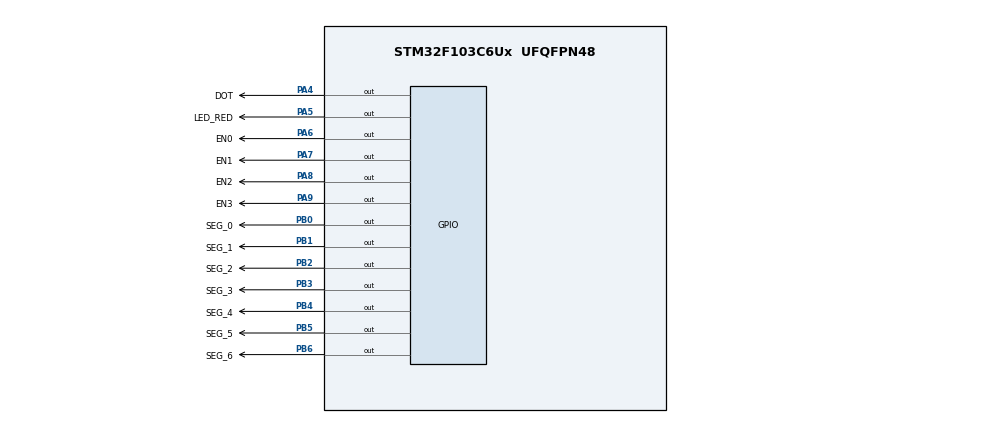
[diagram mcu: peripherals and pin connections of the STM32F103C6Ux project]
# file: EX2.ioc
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Mcu.Family=STM32F1
Mcu.Name=STM32F103C6Ux
Mcu.Package=UFQFPN48
NVIC.PriorityGroup=NVIC_PRIORITYGROUP_4
NVIC.TIM2_IRQn=true\:0\:0\:false\:false\:true\:true\:true
PA4.GPIO_Label=DOT
PA4.Signal=GPIO_Output
PA5.GPIO_Label=LED_RED
PA5.Signal=GPIO_Output
PA6.GPIO_Label=EN0
PA6.Signal=GPIO_Output
PA7.GPIO_Label=EN1
PA7.Signal=GPIO_Output
PA8.GPIO_Label=EN2
PA8.Signal=GPIO_Output
PA9.GPIO_Label=EN3
PA9.Signal=GPIO_Output
PB0.GPIO_Label=SEG_0
PB0.Signal=GPIO_Output
PB1.GPIO_Label=SEG_1
PB1.Signal=GPIO_Output
PB2.GPIO_Label=SEG_2
PB2.Signal=GPIO_Output
PB3.GPIO_Label=SEG_3
PB3.Signal=GPIO_Output
PB4.GPIO_Label=SEG_4
PB4.Signal=GPIO_Output
PB5.GPIO_Label=SEG_5
PB5.Signal=GPIO_Output
PB6.GPIO_Label=SEG_6
PB6.Signal=GPIO_Output
ProjectManager.HeapSize=0x200
ProjectManager.StackSize=0x400
ProjectManager.TargetToolchain=STM32CubeIDE
RCC.APB1Freq_Value=8000000
RCC.APB2Freq_Value=8000000
TIM2.Period=9
TIM2.Prescaler=7999
VP_SYS_VS_ND.Mode=No_Debug
VP_TIM2_VS_ClockSourceINT.Mode=Internal
board=custom

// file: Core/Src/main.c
/* USER CODE BEGIN Header */
/**
  ******************************************************************************
  * @file           : main.c
  * @brief          : Main program body
  ******************************************************************************
  * @attention
  *
  * <h2><center>&copy; Copyright (c) 2022 STMicroelectronics.
  * All rights reserved.</center></h2>
  *
  * This software component is licensed by ST under BSD 3-Clause license,
  * the "License"; You may not use this file except in compliance with the
  * License. You may obtain a copy of the License at:
  *                        opensource.org/licenses/BSD-3-Clause
  *
  ******************************************************************************
  */
/* USER CODE END Header */
#include "main.h"

TIM_HandleTypeDef htim2;

void SystemClock_Config(void);
static void MX_GPIO_Init(void);
static void MX_TIM2_Init(void);

/* USER CODE BEGIN 0 */
void display7SEG(int num){
	  if(num == 0){
		  HAL_GPIO_WritePin(SEG_a_GPIO_Port, SEG_a_Pin, RESET);
		  HAL_GPIO_WritePin(SEG_b_GPIO_Port, SEG_b_Pin, RESET);
		  HAL_GPIO_WritePin(SEG_c_GPIO_Port, SEG_c_Pin, RESET);
		  HAL_GPIO_WritePin(SEG_d_GPIO_Port, SEG_d_Pin, RESET);
		  HAL_GPIO_WritePin(SEG_e_GPIO_Port, SEG_e_Pin, RESET);
		  HAL_GPIO_WritePin(SEG_f_GPIO_Port, SEG_f_Pin, RESET);
		  HAL_GPIO_WritePin(SEG_g_GPIO_Port, SEG_g_Pin, SET);
	  }
	  if(num == 1){
		  HAL_GPIO_WritePin(SEG_a_GPIO_Port, SEG_a_Pin, SET);
		  HAL_GPIO_WritePin(SEG_b_GPIO_Port, SEG_b_Pin, RESET);
		  HAL_GPIO_WritePin(SEG_c_GPIO_Port, SEG_c_Pin, RESET);
		  HAL_GPIO_WritePin(SEG_d_GPIO_Port, SEG_d_Pin, SET);
		  HAL_GPIO_WritePin(SEG_e_GPIO_Port, SEG_e_Pin, SET);
		  HAL_GPIO_WritePin(SEG_f_GPIO_Port, SEG_f_Pin, SET);
		  HAL_GPIO_WritePin(SEG_g_GPIO_Port, SEG_g_Pin, SET);
	  }
	  if(num == 2){
		  HAL_GPIO_WritePin(SEG_a_GPIO_Port, SEG_a_Pin, RESET);
		  HAL_GPIO_WritePin(SEG_b_GPIO_Port, SEG_b_Pin, RESET);
		  HAL_GPIO_WritePin(SEG_c_GPIO_Port, SEG_c_Pin, SET);
		  HAL_GPIO_WritePin(SEG_d_GPIO_Port, SEG_d_Pin, RESET);
		  HAL_GPIO_WritePin(SEG_e_GPIO_Port, SEG_e_Pin, RESET);
		  HAL_GPIO_WritePin(SEG_f_GPIO_Port, SEG_f_Pin, SET);
		  HAL_GPIO_WritePin(SEG_g_GPIO_Port, SEG_g_Pin, RESET);
	  }
	  if(num == 3){
		  HAL_GPIO_WritePin(SEG_a_GPIO_Port, SEG_a_Pin, RESET);
		  HAL_GPIO_WritePin(SEG_b_GPIO_Port, SEG_b_Pin, RESET);
		  HAL_GPIO_WritePin(SEG_c_GPIO_Port, SEG_c_Pin, RESET);
		  HAL_GPIO_WritePin(SEG_d_GPIO_Port, SEG_d_Pin, RESET);
		  HAL_GPIO_WritePin(SEG_e_GPIO_Port, SEG_e_Pin, SET);
		  HAL_GPIO_WritePin(SEG_f_GPIO_Port, SEG_f_Pin, SET);
		  HAL_GPIO_WritePin(SEG_g_GPIO_Port, SEG_g_Pin, RESET);
	  }
	  if(num == 4){
		  HAL_GPIO_WritePin(SEG_a_GPIO_Port, SEG_a_Pin, SET);
		  HAL_GPIO_WritePin(SEG_b_GPIO_Port, SEG_b_Pin, RESET);
		  HAL_GPIO_WritePin(SEG_c_GPIO_Port, SEG_c_Pin, RESET);
		  HAL_GPIO_WritePin(SEG_d_GPIO_Port, SEG_d_Pin, SET);
		  HAL_GPIO_WritePin(SEG_e_GPIO_Port, SEG_e_Pin, SET);
		  HAL_GPIO_WritePin(SEG_f_GPIO_Port, SEG_f_Pin, RESET);
		  HAL_GPIO_WritePin(SEG_g_GPIO_Port, SEG_g_Pin, RESET);
	  }
	  if(num == 5){
		  HAL_GPIO_WritePin(SEG_a_GPIO_Port, SEG_a_Pin, RESET);
		  HAL_GPIO_WritePin(SEG_b_GPIO_Port, SEG_b_Pin, SET);
		  HAL_GPIO_WritePin(SEG_c_GPIO_Port, SEG_c_Pin, RESET);
		  HAL_GPIO_WritePin(SEG_d_GPIO_Port, SEG_d_Pin, RESET);
		  HAL_GPIO_WritePin(SEG_e_GPIO_Port, SEG_e_Pin, SET);
		  HAL_GPIO_WritePin(SEG_f_GPIO_Port, SEG_f_Pin, RESET);
		  HAL_GPIO_WritePin(SEG_g_GPIO_Port, SEG_g_Pin, RESET);
	  }
	  if(num == 6){
		  HAL_GPIO_WritePin(SEG_a_GPIO_Port, SEG_a_Pin, RESET);
		  HAL_GPIO_WritePin(SEG_b_GPIO_Port, SEG_b_Pin, SET);
		  HAL_GPIO_WritePin(SEG_c_GPIO_Port, SEG_c_Pin, RESET);
		  HAL_GPIO_WritePin(SEG_d_GPIO_Port, SEG_d_Pin, RESET);
		  HAL_GPIO_WritePin(SEG_e_GPIO_Port, SEG_e_Pin, RESET);
		  HAL_GPIO_WritePin(SEG_f_GPIO_Port, SEG_f_Pin, RESET);
		  HAL_GPIO_WritePin(SEG_g_GPIO_Port, SEG_g_Pin, RESET);
	  }
	  if(num == 7){
		  HAL_GPIO_WritePin(SEG_a_GPIO_Port, SEG_a_Pin, RESET);
		  HAL_GPIO_WritePin(SEG_b_GPIO_Port, SEG_b_Pin, RESET);
		  HAL_GPIO_WritePin(SEG_c_GPIO_Port, SEG_c_Pin, RESET);
		  HAL_GPIO_WritePin(SEG_d_GPIO_Port, SEG_d_Pin, SET);
		  HAL_GPIO_WritePin(SEG_e_GPIO_Port, SEG_e_Pin, SET);
		  HAL_GPIO_WritePin(SEG_f_GPIO_Port, SEG_f_Pin, SET);
		  HAL_GPIO_WritePin(SEG_g_GPIO_Port, SEG_g_Pin, SET);
	  }
	  if(num == 8){
		  HAL_GPIO_WritePin(SEG_a_GPIO_Port, SEG_a_Pin, RESET);
		  HAL_GPIO_WritePin(SEG_b_GPIO_Port, SEG_b_Pin, RESET);
		  HAL_GPIO_WritePin(SEG_c_GPIO_Port, SEG_c_Pin, RESET);
		  HAL_GPIO_WritePin(SEG_d_GPIO_Port, SEG_d_Pin, RESET);
		  HAL_GPIO_WritePin(SEG_e_GPIO_Port, SEG_e_Pin, RESET);
		  HAL_GPIO_WritePin(SEG_f_GPIO_Port, SEG_f_Pin, RESET);
		  HAL_GPIO_WritePin(SEG_g_GPIO_Port, SEG_g_Pin, RESET);
	  }
	  if(num == 9){
		  HAL_GPIO_WritePin(SEG_a_GPIO_Port, SEG_a_Pin, RESET);
		  HAL_GPIO_WritePin(SEG_b_GPIO_Port, SEG_b_Pin, RESET);
		  HAL_GPIO_WritePin(SEG_c_GPIO_Port, SEG_c_Pin, RESET);
		  HAL_GPIO_WritePin(SEG_d_GPIO_Port, SEG_d_Pin, RESET);
		  HAL_GPIO_WritePin(SEG_e_GPIO_Port, SEG_e_Pin, SET);
		  HAL_GPIO_WritePin(SEG_f_GPIO_Port, SEG_f_Pin, RESET);
		  HAL_GPIO_WritePin(SEG_g_GPIO_Port, SEG_g_Pin, RESET);
	  }
}
const int MAX_LED = 4;
int index_led = 0;
int led_buffer [4] = {1 , 2 , 3 , 4};
void update7SEG(int index){
	index = index % MAX_LED;
	switch(index){
	case 0:
		HAL_GPIO_WritePin(EN0_GPIO_Port, EN0_Pin, RESET);
		HAL_GPIO_WritePin(EN1_GPIO_Port, EN1_Pin, SET);
		HAL_GPIO_WritePin(EN2_GPIO_Port, EN2_Pin, SET);
		HAL_GPIO_WritePin(EN3_GPIO_Port, EN3_Pin, SET);
		display7SEG(led_buffer[0]);
		break;
	case 1:
		HAL_GPIO_WritePin(EN0_GPIO_Port, EN0_Pin, SET);
		HAL_GPIO_WritePin(EN1_GPIO_Port, EN1_Pin, RESET);
		HAL_GPIO_WritePin(EN2_GPIO_Port, EN2_Pin, SET);
		HAL_GPIO_WritePin(EN3_GPIO_Port, EN3_Pin, SET);
		display7SEG(led_buffer[1]);
		break;
	case 2:
		HAL_GPIO_WritePin(EN0_GPIO_Port, EN0_Pin, SET);
		HAL_GPIO_WritePin(EN1_GPIO_Port, EN1_Pin, SET);
		HAL_GPIO_WritePin(EN2_GPIO_Port, EN2_Pin, RESET);
		HAL_GPIO_WritePin(EN3_GPIO_Port, EN3_Pin, SET);
		display7SEG(led_buffer[2]);
		break;
	case 3:
		HAL_GPIO_WritePin(EN0_GPIO_Port, EN0_Pin, SET);
		HAL_GPIO_WritePin(EN1_GPIO_Port, EN1_Pin, SET);
		HAL_GPIO_WritePin(EN2_GPIO_Port, EN2_Pin, SET);
		HAL_GPIO_WritePin(EN3_GPIO_Port, EN3_Pin, RESET);
		display7SEG(led_buffer[3]);
		break;
	default:
		index = 0;
		break;
	}
}
void updateClockBuffer(int hour, int minute, int* led_buffer){
	led_buffer[0] = hour / 10;
	led_buffer[1] = hour % 10;
	led_buffer[2] = minute / 10;
	led_buffer[3] = minute % 10;
}

int timer0_counter = 0;
int timer0_flag = 0;
int timer1_counter = 0;
int timer1_flag = 0;

int TIMER_CYCLE = 10;
void setTimer0(int duration){
	timer0_counter = duration / TIMER_CYCLE;
	timer0_flag = 0;
}
void setTimer1(int duration){
	timer1_counter = duration / TIMER_CYCLE;
	timer1_flag = 0;
}
void timerRun(){
	if(timer0_counter > 0){
		timer0_counter--;
		if(timer0_counter == 0){
			timer0_flag = 1;
		}
	}
	if(timer1_counter > 0){
		timer1_counter--;
		if(timer1_counter == 0){
			timer1_flag = 1;
		}
	}
}
/* USER CODE END 0 */

int main(void)
{

  /* MCU Configuration--------------------------------------------------------*/

  /* Reset of all peripherals, Initializes the Flash interface and the Systick. */
  HAL_Init();

  /* Configure the system clock */
  SystemClock_Config();

  /* Initialize all configured peripherals */
  MX_GPIO_Init();
  MX_TIM2_Init();
  /* USER CODE BEGIN 2 */
  HAL_TIM_Base_Start_IT(&htim2);
  /* USER CODE END 2 */

  /* Infinite loop */
  /* USER CODE BEGIN WHILE */
  int hour = 15, minute = 18, second = 50;
  setTimer0(1000);
  setTimer1(250);
  while (1)
  {
	  if(timer0_flag == 1){
		  second++;
		  if(second >= 60){
			  second = 0;
			  minute++;
		  }
		  if(minute >= 60){
			  minute = 0;
			  hour++;
		  }
		  if(hour >= 24){
			  hour = 0;
		  }
		  updateClockBuffer(hour, minute, led_buffer);
		  HAL_GPIO_TogglePin(DOT_GPIO_Port, DOT_Pin);
		  HAL_GPIO_TogglePin(RED_GPIO_Port, RED_Pin);
		  setTimer0(1000);
	  }
	  if(timer1_flag == 1){
		  index_led++;
		  update7SEG(index_led);
		  setTimer1(250);
	  }

    /* USER CODE END WHILE */

  }
}

void SystemClock_Config(void)
{
  RCC_OscInitTypeDef RCC_OscInitStruct = {0};
  RCC_ClkInitTypeDef RCC_ClkInitStruct = {0};

  /** Initializes the RCC Oscillators according to the specified parameters
  * in the RCC_OscInitTypeDef structure.
  */
  RCC_OscInitStruct.OscillatorType = RCC_OSCILLATORTYPE_HSI;
  RCC_OscInitStruct.HSIState = RCC_HSI_ON;
  RCC_OscInitStruct.HSICalibrationValue = RCC_HSICALIBRATION_DEFAULT;
  RCC_OscInitStruct.PLL.PLLState = RCC_PLL_NONE;
  if (HAL_RCC_OscConfig(&RCC_OscInitStruct) != HAL_OK)
  {
    Error_Handler();
  }
  /** Initializes the CPU, AHB and APB buses clocks
  */
  RCC_ClkInitStruct.ClockType = RCC_CLOCKTYPE_HCLK|RCC_CLOCKTYPE_SYSCLK
                              |RCC_CLOCKTYPE_PCLK1|RCC_CLOCKTYPE_PCLK2;
  RCC_ClkInitStruct.SYSCLKSource = RCC_SYSCLKSOURCE_HSI;
  RCC_ClkInitStruct.AHBCLKDivider = RCC_SYSCLK_DIV1;
  RCC_ClkInitStruct.APB1CLKDivider = RCC_HCLK_DIV1;
  RCC_ClkInitStruct.APB2CLKDivider = RCC_HCLK_DIV1;

  if (HAL_RCC_ClockConfig(&RCC_ClkInitStruct, FLASH_LATENCY_0) != HAL_OK)
  {
    Error_Handler();
  }
}

static void MX_TIM2_Init(void)
{

  TIM_ClockConfigTypeDef sClockSourceConfig = {0};
  TIM_MasterConfigTypeDef sMasterConfig = {0};

  htim2.Instance = TIM2;
  htim2.Init.Prescaler = 7999;
  htim2.Init.CounterMode = TIM_COUNTERMODE_UP;
  htim2.Init.Period = 9;
  htim2.Init.ClockDivision = TIM_CLOCKDIVISION_DIV1;
  htim2.Init.AutoReloadPreload = TIM_AUTORELOAD_PRELOAD_DISABLE;
  if (HAL_TIM_Base_Init(&htim2) != HAL_OK)
  {
    Error_Handler();
  }
  sClockSourceConfig.ClockSource = TIM_CLOCKSOURCE_INTERNAL;
  if (HAL_TIM_ConfigClockSource(&htim2, &sClockSourceConfig) != HAL_OK)
  {
    Error_Handler();
  }
  sMasterConfig.MasterOutputTrigger = TIM_TRGO_RESET;
  sMasterConfig.MasterSlaveMode = TIM_MASTERSLAVEMODE_DISABLE;
  if (HAL_TIMEx_MasterConfigSynchronization(&htim2, &sMasterConfig) != HAL_OK)
  {
    Error_Handler();
  }

}

static void MX_GPIO_Init(void)
{
  GPIO_InitTypeDef GPIO_InitStruct = {0};

  /* GPIO Ports Clock Enable */
  __HAL_RCC_GPIOA_CLK_ENABLE();
  __HAL_RCC_GPIOB_CLK_ENABLE();

  /*Configure GPIO pin Output Level */
  HAL_GPIO_WritePin(GPIOA, DOT_Pin|RED_Pin|EN0_Pin|EN1_Pin
                          |EN2_Pin|EN3_Pin, GPIO_PIN_RESET);

  /*Configure GPIO pin Output Level */
  HAL_GPIO_WritePin(GPIOB, SEG_a_Pin|SEG_b_Pin|SEG_c_Pin|SEG_d_Pin
                          |SEG_e_Pin|SEG_f_Pin|SEG_g_Pin, GPIO_PIN_RESET);

  /*Configure GPIO pins : DOT_Pin RED_Pin EN0_Pin EN1_Pin
                           EN2_Pin EN3_Pin */
  GPIO_InitStruct.Pin = DOT_Pin|RED_Pin|EN0_Pin|EN1_Pin
                          |EN2_Pin|EN3_Pin;
  GPIO_InitStruct.Mode = GPIO_MODE_OUTPUT_PP;
  GPIO_InitStruct.Pull = GPIO_NOPULL;
  GPIO_InitStruct.Speed = GPIO_SPEED_FREQ_LOW;
  HAL_GPIO_Init(GPIOA, &GPIO_InitStruct);

  /*Configure GPIO pins : SEG_a_Pin SEG_b_Pin SEG_c_Pin SEG_d_Pin
                           SEG_e_Pin SEG_f_Pin SEG_g_Pin */
  GPIO_InitStruct.Pin = SEG_a_Pin|SEG_b_Pin|SEG_c_Pin|SEG_d_Pin
                          |SEG_e_Pin|SEG_f_Pin|SEG_g_Pin;
  GPIO_InitStruct.Mode = GPIO_MODE_OUTPUT_PP;
  GPIO_InitStruct.Pull = GPIO_NOPULL;
  GPIO_InitStruct.Speed = GPIO_SPEED_FREQ_LOW;
  HAL_GPIO_Init(GPIOB, &GPIO_InitStruct);

}

/* USER CODE BEGIN 4 */
void HAL_TIM_PeriodElapsedCallback(TIM_HandleTypeDef * htim){
	timerRun();
}
/* USER CODE END 4 */

void Error_Handler(void)
{
  __disable_irq();
  while (1)
  {
  }
}

/************************ (C) COPYRIGHT STMicroelectronics *****END OF FILE****/
